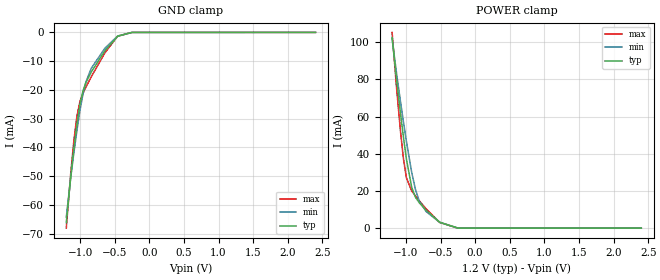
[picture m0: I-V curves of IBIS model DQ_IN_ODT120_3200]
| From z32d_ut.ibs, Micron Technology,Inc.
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| MODEL DQ_IN_ODT120_3200 (Data Input with 120ohm ODT, 1600-3200Mbps)
[Model]   DQ_IN_ODT120_3200
Model_type   Input
Vinl = 905.000mV
Vinh = 1015.000mV
|   typ   min   max
|C_comp   0.616pF   0.564pF   0.668pF
C_comp_power_clamp   0.308pF   0.282pF   0.334pF
C_comp_gnd_clamp   0.308pF   0.282pF   0.334pF
| Note: C_comp changes when the ODT circuit is enabled.
|[Model Spec]
| Dynamic Overshoot Parameters from DDR4 Specification
|D_overshoot_ampl_h   0.40   NA   NA
|D_overshoot_ampl_l   0.40   NA   NA
|D_overshoot_area_h   0.0800n   NA   NA
|D_overshoot_area_l   0.0800n   NA   NA
[Voltage Range]   1.2000V   1.1400V   1.2600V
| Junction Temperature (Ambient temp is 35C typ, 125C min, -40C max)
[Temperature Range]   50.0   140.0   -40.0
[Add Submodel]
| Submodel Name   Mode
120ohm_ODT_3200   Non-Driving
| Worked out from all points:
|   GND clamp passes 1 mA (typ) near -0.44 V on its own axis
|   POWER clamp passes 1 mA (typ) near -0.41 V on its own axis
[GND Clamp]
|   Voltage   I(typ)   I(min)   I(max)
-1.2V     -66.16mA   -64.28mA   -68.09mA
-1.135V   -50.09mA   -50.4mA    -48.84mA
-1.091V   -40.54mA   -42.05mA   -37.85mA
-1.047V   -32.06mA   -34.29mA   -29.28mA
-1.004V   -25.24mA   -27.37mA   -24.15mA
-960mV    -20.46mA   -21.61mA   -21.27mA
-916.4mV  -17.45mA   -17.25mA   -19.05mA
-840mV    -13.84mA   -12.54mA   -15.5mA
-643.6mV  -6.426mA   -5.55mA    -7.18mA
-458.2mV  -1.359mA   -1.253mA   -1.332mA
-250.9mV  -9.002uA   -25.19uA   1.741uA
2.4V      0A         0A         0A
[POWER Clamp]
|   Voltage   I(typ)   I(min)   I(max)
-1.2V     102.5mA    102mA      105.3mA
-1.135V   79.77mA    83.1mA     75.19mA
-1.08V    62.13mA    68.42mA    52.54mA
-1.036V   48.91mA    57.17mA    37.32mA
-992.7mV  37.04mA    46.51mA    27.02mA
-916.4mV  21.89mA    29.93mA    20mA
-861.8mV  16.57mA    20.7mA     17.26mA
-807.3mV  13.63mA    14.48mA    14.72mA
-709.1mV  9.665mA    8.958mA    10.4mA
-512.7mV  3.198mA    3.102mA    3.061mA
-250.9mV  21.9uA     63.81uA    -1.736uA
2.4V      0A         0A         0A
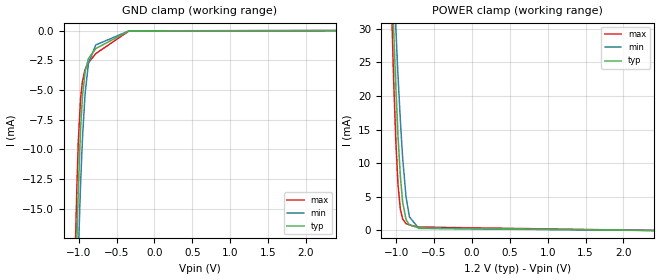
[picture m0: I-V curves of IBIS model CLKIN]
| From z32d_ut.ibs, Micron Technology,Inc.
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| MODEL CLKIN (Clock Input Model, 1600-3200Mbps)
[Model]   CLKIN
Model_type   Input
Vinl = 510.000mV
Vinh = 690.000mV
|   typ   min   max
|C_comp   0.414pF   0.364pF   0.464pF
C_comp_power_clamp   0.207pF   0.182pF   0.232pF
C_comp_gnd_clamp   0.207pF   0.182pF   0.232pF
[Model Spec]
| Input threshold voltage corners
Vinl   0.5100V   0.4800V   0.5400V
Vinh   0.6900V   0.6600V   0.7200V
| Dynamic Overshoot Parameters from DDR4 Specification
|D_overshoot_ampl_h   0.30   NA   NA
|D_overshoot_ampl_l   0.30   NA   NA
|D_overshoot_area_h   0.0775n   NA   NA
|D_overshoot_area_l   0.0762n   NA   NA
[Receiver Thresholds]
|Vth   =  0.600V
|Vth_min  =  0.5880V
|Vth_max  =  0.6120V
|Vinh_ac  =  0.090V
|Vinh_dc  =  0.060V
|Vinl_ac  = -0.090V
|Vinl_dc  = -0.060V
|Tslew_ac =  5.000ns |Not specified, so set to high value
|Threshold_sensitivity = 0.50
|Reference_supply Power_clamp_ref
|NOTE: If using the IBISCHK 4.2.1 or older parser, Differential receiver
|threshold parameters must be commented out because the parser generates
|errors for multiple differential models.
Vcross_low   = 0.460V
Vcross_high  = 0.740V
Vdiff_ac   = 180mV
Vdiff_dc   = 150mV
Tdiffslew_ac = 10.000ns |Not specified, so set to high value
[Voltage Range]   1.2000V   1.1400V   1.2600V
[POWER Clamp Reference]   1.2000V   1.1400V   1.2600V
| Junction Temperature (Ambient temp is 35C typ, 125C min, -40C max)
[Temperature Range]   50.0   140.0   -40.0
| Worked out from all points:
|   GND clamp passes 1 mA (typ) near -0.68 V on its own axis
|   POWER clamp passes 1 mA (typ) near -0.84 V on its own axis
[GND Clamp]
|   Voltage   I(typ)   I(min)   I(max)
-1.2V     -78.53mA   -76.01mA   -84.87mA
-1.06V    -27.54mA   -32.43mA   -23.15mA
-1.045V   -23.16mA   -28.42mA   -18.65mA
-1.025V   -17.89mA   -23.42mA   -13.45mA
-1.005V   -13.38mA   -18.85mA   -9.34mA
-975mV    -8.281mA   -12.94mA   -5.706mA
-950mV    -5.533mA   -9.09mA    -4.258mA
-915mV    -3.441mA   -5.261mA   -3.282mA
-870mV    -2.342mA   -2.735mA   -2.705mA
-775mV    -1.518mA   -1.213mA   -1.941mA
-335mV    -23.32uA   -17.18uA   -29.39uA
2.4V      0A         0A         0A
[POWER Clamp]
|   Voltage   I(typ)   I(min)   I(max)
-1.2V     91.17mA    87.49mA    102.2mA
-1.115V   58.2mA     61.1mA     58mA
-1.065V   40.26mA    46.42mA    34.89mA
-1.035V   30.37mA    38.07mA    22.88mA
-1.005V   21.43mA    30.16mA    13.33mA
-975mV    13.85mA    22.85mA    6.683mA
-945mV    8.11mA     16.37mA    3.182mA
-915mV    4.241mA    10.84mA    1.715mA
-870mV    1.619mA    5.002mA    1.03mA
-825mV    825.6uA    2.02mA     820.5uA
-700mV    367.4uA    304.9uA    509.9uA
2.4V      0A         0A         0A
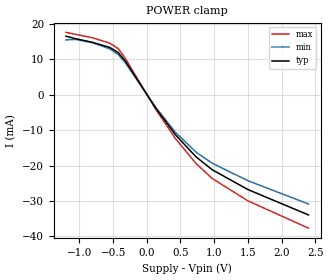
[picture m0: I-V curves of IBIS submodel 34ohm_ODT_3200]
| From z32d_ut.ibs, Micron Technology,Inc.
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| SUBMODEL 34ohm_ODT_3200
[Submodel]   34ohm_ODT_3200
Submodel_type  Dynamic_clamp
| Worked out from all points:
|   POWER clamp passes 1 mA (typ) near -0.03 V on its own axis
[POWER Clamp]
|   Voltage   I(typ)   I(min)   I(max)
-1.2V     16.56mA    15.53mA    17.64mA
-1.05V    15.82mA    15.64mA    17.05mA
-810mV    14.85mA    14.73mA    16.13mA
-550mV    13.39mA    12.98mA    14.6mA
-425mV    11.94mA    11.39mA    13.06mA
-320mV    9.561mA    9.114mA    10.33mA
130mV     -3.68mA    -3.481mA   -4.014mA
425mV     -11.28mA   -10.59mA   -12.35mA
730mV     -17.5mA    -16.18mA   -19.39mA
970mV     -21.15mA   -19.31mA   -23.63mA
1.5V      -26.75mA   -24.25mA   -29.94mA
2.4V      -33.93mA   -30.84mA   -37.66mA
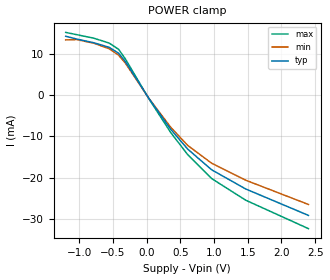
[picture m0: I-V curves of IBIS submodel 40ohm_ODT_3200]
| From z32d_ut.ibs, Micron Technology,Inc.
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| SUBMODEL 40ohm_ODT_3200
[Submodel]   40ohm_ODT_3200
Submodel_type  Dynamic_clamp
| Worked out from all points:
|   POWER clamp passes 1 mA (typ) near -0.04 V on its own axis
[POWER Clamp]
|   Voltage   I(typ)   I(min)   I(max)
-1.2V     14.19mA    13.31mA    15.12mA
-1.035V   13.51mA    13.38mA    14.57mA
-780mV    12.61mA    12.49mA    13.71mA
-555mV    11.51mA    11.17mA    12.54mA
-415mV    10.09mA    9.616mA    11.03mA
-315mV    8.073mA    7.699mA    8.719mA
35mV      -861.2uA   -817.8uA   -934.6uA
360mV     -8.328mA   -7.838mA   -9.117mA
610mV     -13.08mA   -12.18mA   -14.41mA
965mV     -18.07mA   -16.49mA   -20.19mA
1.47V     -22.7mA    -20.58mA   -25.41mA
2.4V      -29.08mA   -26.44mA   -32.28mA
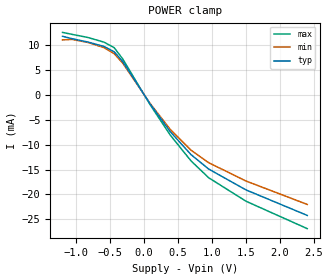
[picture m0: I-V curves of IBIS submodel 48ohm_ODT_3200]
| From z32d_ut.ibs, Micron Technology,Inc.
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| SUBMODEL 48ohm_ODT_3200
[Submodel]   48ohm_ODT_3200
Submodel_type  Dynamic_clamp
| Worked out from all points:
|   POWER clamp passes 1 mA (typ) near -0.05 V on its own axis
[POWER Clamp]
|   Voltage   I(typ)   I(min)   I(max)
-1.2V     11.82mA    11.09mA    12.6mA
-1.065V   11.35mA    11.19mA    12.22mA
-830mV    10.67mA    10.59mA    11.59mA
-590mV    9.773mA    9.528mA    10.64mA
-440mV    8.7mA      8.313mA    9.523mA
-315mV    6.729mA    6.418mA    7.263mA
90mV      -1.831mA   -1.735mA   -1.994mA
385mV     -7.382mA   -6.936mA   -8.075mA
690mV     -12mA      -11.11mA   -13.26mA
950mV     -14.91mA   -13.63mA   -16.66mA
1.5V      -19.11mA   -17.32mA   -21.39mA
2.4V      -24.24mA   -22.03mA   -26.9mA
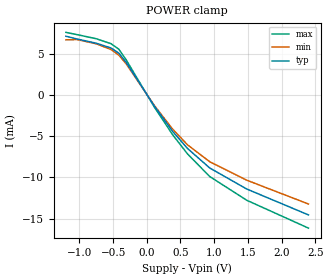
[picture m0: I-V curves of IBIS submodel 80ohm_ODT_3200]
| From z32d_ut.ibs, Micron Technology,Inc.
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| SUBMODEL 80ohm_ODT_3200
[Submodel]   80ohm_ODT_3200
Submodel_type  Dynamic_clamp
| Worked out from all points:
|   POWER clamp passes 1 mA (typ) near -0.08 V on its own axis
[POWER Clamp]
|   Voltage   I(typ)   I(min)   I(max)
-1.2V     7.095mA    6.655mA    7.561mA
-1.035V   6.757mA    6.691mA    7.287mA
-750mV    6.248mA    6.176mA    6.791mA
-530mV    5.667mA    5.482mA    6.187mA
-415mV    5.042mA    4.808mA    5.517mA
-305mV    3.916mA    3.74mA     4.223mA
115mV     -1.399mA   -1.324mA   -1.524mA
385mV     -4.433mA   -4.161mA   -4.848mA
605mV     -6.5mA     -6.057mA   -7.158mA
935mV     -8.863mA   -8.105mA   -9.898mA
1.485V    -11.41mA   -10.34mA   -12.77mA
2.4V      -14.54mA   -13.22mA   -16.14mA
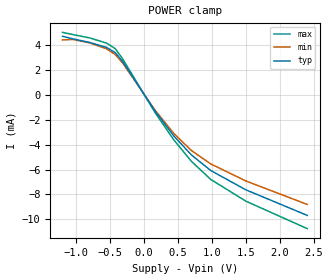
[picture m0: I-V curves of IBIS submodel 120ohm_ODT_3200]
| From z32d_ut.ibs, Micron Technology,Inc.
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| SUBMODEL 120ohm_ODT_3200
[Submodel]   120ohm_ODT_3200
Submodel_type  Dynamic_clamp
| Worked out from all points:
|   POWER clamp passes 1 mA (typ) near -0.12 V on its own axis
[POWER Clamp]
|   Voltage   I(typ)   I(min)   I(max)
-1.2V     4.73mA     4.436mA    5.04mA
-1.05V    4.521mA    4.47mA     4.872mA
-800mV    4.231mA    4.194mA    4.596mA
-550mV    3.825mA    3.711mA    4.172mA
-425mV    3.414mA    3.259mA    3.735mA
-320mV    2.733mA    2.608mA    2.952mA
160mV     -1.289mA   -1.216mA   -1.407mA
435mV     -3.286mA   -3.088mA   -3.601mA
695mV     -4.822mA   -4.467mA   -5.336mA
980mV     -6.079mA   -5.549mA   -6.798mA
1.495V    -7.63mA    -6.918mA   -8.542mA
2.4V      -9.695mA   -8.813mA   -10.76mA
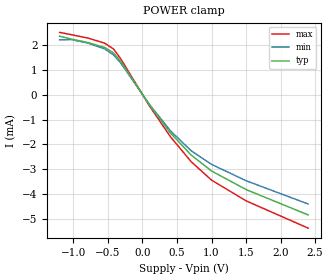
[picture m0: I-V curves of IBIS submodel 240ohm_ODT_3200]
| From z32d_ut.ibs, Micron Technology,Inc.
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| SUBMODEL 240ohm_ODT_3200
[Submodel]   240ohm_ODT_3200
Submodel_type  Dynamic_clamp
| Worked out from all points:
|   POWER clamp passes 1 mA (typ) near -0.23 V on its own axis
[POWER Clamp]
|   Voltage   I(typ)   I(min)   I(max)
-1.2V     2.366mA    2.219mA    2.521mA
-1.035V   2.253mA    2.231mA    2.43mA
-790mV    2.11mA     2.09mA     2.292mA
-550mV    1.913mA    1.857mA    2.087mA
-420mV    1.694mA    1.615mA    1.854mA
-315mV    1.347mA    1.285mA    1.454mA
100mV     -407uA     -385.4uA   -442.4uA
405mV     -1.538mA   -1.452mA   -1.692mA
705mV     -2.43mA    -2.257mA   -2.697mA
1V        -3.073mA   -2.807mA   -3.442mA
1.505V    -3.829mA   -3.471mA   -4.285mA
2.4V      -4.847mA   -4.406mA   -5.38mA
